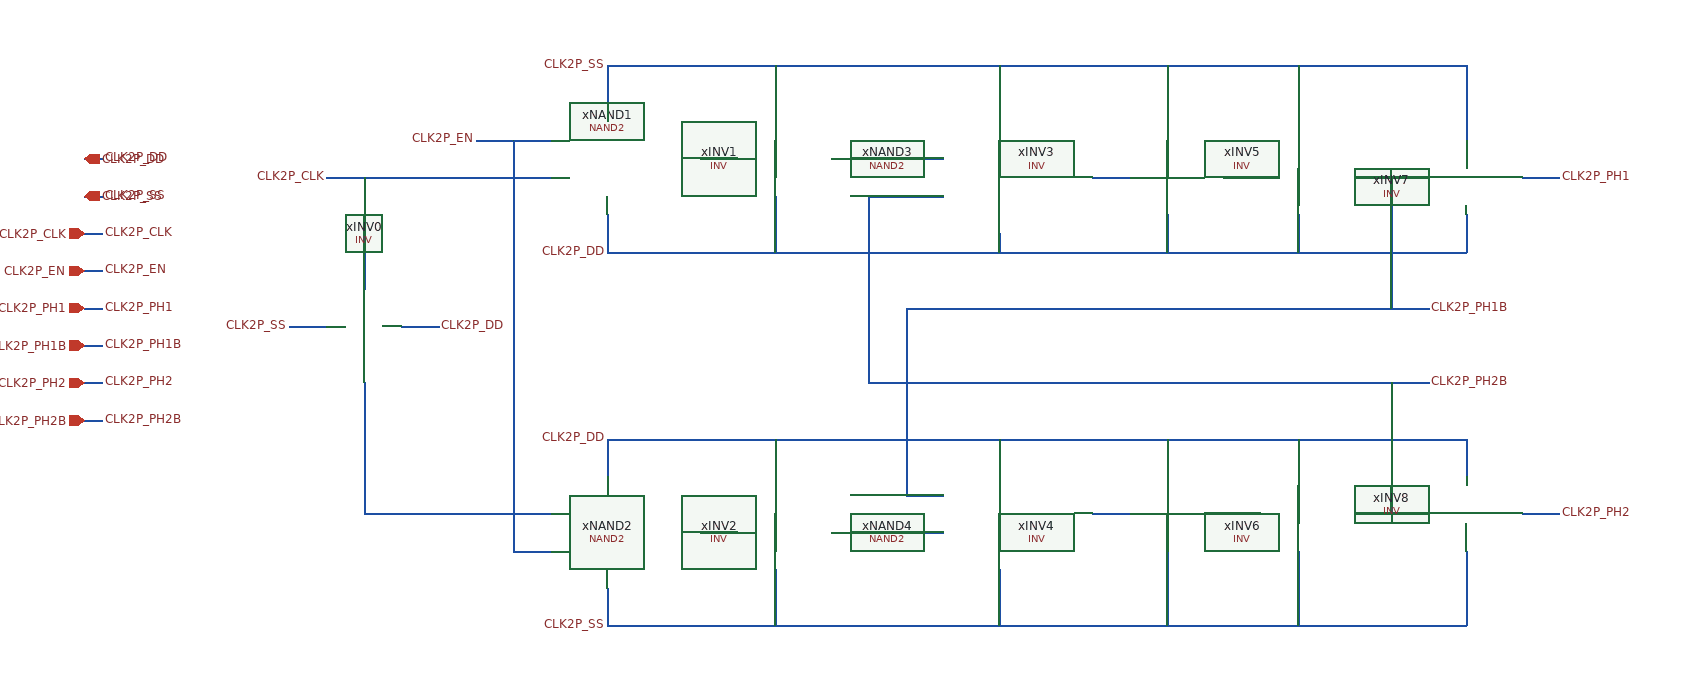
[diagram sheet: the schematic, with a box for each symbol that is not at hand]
v {xschem version=3.4.8RC file_version=1.3}
G {}
K {}
V {}
S {}
F {}
E {}
N 140 -660 160 -660 {lab=CLK2P_DD}
N 140 -620 160 -620 {lab=CLK2P_SS}
N 140 -580 160 -580 {lab=CLK2P_CLK}
N 140 -540 160 -540 {lab=CLK2P_EN}
N 140 -500 160 -500 {lab=CLK2P_PH1}
N 140 -460 160 -460 {lab=CLK2P_PH1B}
N 140 -420 160 -420 {lab=CLK2P_PH2}
N 140 -380 160 -380 {lab=CLK2P_PH2B}
N 700 -760 700 -720 {lab=CLK2P_SS}
N 700 -200 700 -160 {lab=CLK2P_SS}
N 700 -360 700 -320 {lab=CLK2P_DD}
N 700 -600 700 -560 {lab=CLK2P_DD}
N 800 -660 840 -660 {lab=#net1}
N 800 -260 840 -260 {lab=#net2}
N 560 -680 640 -680 {lab=#net3}
N 400 -640 640 -640 {lab=CLK2P_CLK}
N 440 -280 640 -280 {lab=#net4}
N 440 -640 440 -520 {lab=CLK2P_CLK}
N 360 -480 400 -480 {lab=CLK2P_SS}
N 480 -480 520 -480 {lab=CLK2P_DD}
N 1220 -640 1260 -640 {lab=#net5}
N 1220 -280 1260 -280 {lab=#net6}
N 1300 -600 1300 -560 {lab=CLK2P_DD}
N 1300 -360 1300 -320 {lab=CLK2P_DD}
N 1360 -640 1400 -640 {lab=#net7}
N 1360 -280 1400 -280 {lab=#net8}
N 1440 -600 1440 -560 {lab=CLK2P_DD}
N 1440 -360 1440 -320 {lab=CLK2P_DD}
N 440 -420 440 -280 {lab=#net4}
N 1500 -640 1580 -640 {lab=CLK2P_PH1B}
N 1500 -280 1580 -280 {lab=CLK2P_PH2B}
N 1620 -600 1620 -560 {lab=CLK2P_DD}
N 1620 -360 1620 -320 {lab=CLK2P_DD}
N 1680 -640 1720 -640 {lab=CLK2P_PH1}
N 1680 -280 1720 -280 {lab=CLK2P_PH2}
N 1020 -300 1060 -300 {lab=CLK2P_PH1B}
N 980 -620 1060 -620 {lab=CLK2P_PH2B}
N 940 -260 1060 -260 {lab=#net9}
N 940 -660 1060 -660 {lab=#net10}
N 980 -620 980 -420 {lab=CLK2P_PH2B}
N 1020 -500 1020 -300 {lab=CLK2P_PH1B}
N 1540 -640 1540 -500 {lab=CLK2P_PH1B}
N 1540 -420 1540 -280 {lab=CLK2P_PH2B}
N 980 -420 1580 -420 {lab=CLK2P_PH2B}
N 1020 -500 1580 -500 {lab=CLK2P_PH1B}
N 880 -360 880 -300 {lab=CLK2P_DD}
N 1120 -360 1120 -340 {lab=CLK2P_DD}
N 700 -360 1620 -360 {lab=CLK2P_DD}
N 880 -620 880 -560 {lab=CLK2P_DD}
N 1120 -580 1120 -560 {lab=CLK2P_DD}
N 700 -560 1620 -560 {lab=CLK2P_DD}
N 880 -220 880 -160 {lab=CLK2P_SS}
N 1120 -220 1120 -160 {lab=CLK2P_SS}
N 1300 -240 1300 -160 {lab=CLK2P_SS}
N 1440 -240 1440 -160 {lab=CLK2P_SS}
N 1620 -240 1620 -160 {lab=CLK2P_SS}
N 700 -160 1620 -160 {lab=CLK2P_SS}
N 1300 -760 1300 -680 {lab=CLK2P_SS}
N 1440 -760 1440 -680 {lab=CLK2P_SS}
N 1620 -760 1620 -680 {lab=CLK2P_SS}
N 1120 -760 1120 -700 {lab=CLK2P_SS}
N 880 -760 880 -700 {lab=CLK2P_SS}
N 700 -760 1620 -760 {lab=CLK2P_SS}
N 600 -240 640 -240 {lab=#net3}
N 600 -680 600 -240 {lab=#net3}
C {title.sym} 160 -40 0 0 {name=l1 author="Yi-Hsiang Wei"}
C {iopin.sym} 140 -660 0 1 {name=p8 lab=CLK2P_DD}
C {iopin.sym} 140 -620 0 1 {name=p9 lab=CLK2P_SS}
C {lab_wire.sym} 160 -660 0 1 {name=p11 sig_type=std_logic lab=CLK2P_DD}
C {lab_wire.sym} 160 -620 0 1 {name=p12 sig_type=std_logic lab=CLK2P_SS}
C {ipin.sym} 140 -580 0 0 {name=p13 lab=CLK2P_CLK}
C {lab_wire.sym} 160 -580 0 1 {name=p15 sig_type=std_logic lab=CLK2P_CLK}
C {ECG_Acquisition_IC/Design_Files/IC Design/Schematic/INV/INV.sym} 340 -600 1 0 {name=xINV0}
C {lab_wire.sym} 400 -640 0 0 {name=p5 sig_type=std_logic lab=CLK2P_CLK}
C {ipin.sym} 140 -540 0 0 {name=p1 lab=CLK2P_EN}
C {lab_wire.sym} 160 -540 0 1 {name=p2 sig_type=std_logic lab=CLK2P_EN}
C {opin.sym} 140 -500 0 1 {name=p3 lab=CLK2P_PH1}
C {lab_wire.sym} 160 -500 0 1 {name=p4 sig_type=std_logic lab=CLK2P_PH1}
C {opin.sym} 140 -460 0 1 {name=p6 lab=CLK2P_PH1B}
C {lab_wire.sym} 160 -460 0 1 {name=p7 sig_type=std_logic lab=CLK2P_PH1B}
C {opin.sym} 140 -420 0 1 {name=p10 lab=CLK2P_PH2}
C {lab_wire.sym} 160 -420 0 1 {name=p14 sig_type=std_logic lab=CLK2P_PH2}
C {opin.sym} 140 -380 0 1 {name=p16 lab=CLK2P_PH2B}
C {lab_wire.sym} 160 -380 0 1 {name=p17 sig_type=std_logic lab=CLK2P_PH2B}
C {ECG_Acquisition_IC/Design_Files/IC Design/Schematic/NAND2/NAND2.sym} 560 -740 2 1 {name=xNAND1}
C {ECG_Acquisition_IC/Design_Files/IC Design/Schematic/NAND2/NAND2.sym} 560 -180 0 0 {name=xNAND2}
C {ECG_Acquisition_IC/Design_Files/IC Design/Schematic/INV/INV.sym} 760 -760 2 1 {name=xINV1}
C {ECG_Acquisition_IC/Design_Files/IC Design/Schematic/INV/INV.sym} 760 -160 0 0 {name=xINV2}
C {lab_wire.sym} 560 -680 0 0 {name=p18 sig_type=std_logic lab=CLK2P_EN}
C {ECG_Acquisition_IC/Design_Files/IC Design/Schematic/NAND2/NAND2.sym} 980 -720 2 1 {name=xNAND3}
C {ECG_Acquisition_IC/Design_Files/IC Design/Schematic/NAND2/NAND2.sym} 980 -200 0 0 {name=xNAND4}
C {ECG_Acquisition_IC/Design_Files/IC Design/Schematic/INV/INV.sym} 1180 -740 2 1 {name=xINV3}
C {ECG_Acquisition_IC/Design_Files/IC Design/Schematic/INV/INV.sym} 1180 -180 0 0 {name=xINV4}
C {ECG_Acquisition_IC/Design_Files/IC Design/Schematic/INV/INV.sym} 1320 -740 2 1 {name=xINV5}
C {ECG_Acquisition_IC/Design_Files/IC Design/Schematic/INV/INV.sym} 1320 -180 0 0 {name=xINV6}
C {lab_wire.sym} 1580 -500 2 0 {name=p20 sig_type=std_logic lab=CLK2P_PH1B}
C {ECG_Acquisition_IC/Design_Files/IC Design/Schematic/INV/INV.sym} 1500 -740 2 1 {name=xINV7}
C {ECG_Acquisition_IC/Design_Files/IC Design/Schematic/INV/INV.sym} 1500 -180 0 0 {name=xINV8}
C {lab_wire.sym} 1580 -420 0 1 {name=p21 sig_type=std_logic lab=CLK2P_PH2B}
C {lab_wire.sym} 1720 -280 2 0 {name=p22 sig_type=std_logic lab=CLK2P_PH2}
C {lab_wire.sym} 1720 -640 0 1 {name=p23 sig_type=std_logic lab=CLK2P_PH1}
C {lab_wire.sym} 700 -360 0 0 {name=p24 sig_type=std_logic lab=CLK2P_DD}
C {lab_wire.sym} 700 -560 2 1 {name=p25 sig_type=std_logic lab=CLK2P_DD}
C {lab_wire.sym} 700 -160 2 1 {name=p26 sig_type=std_logic lab=CLK2P_SS}
C {lab_wire.sym} 700 -760 0 0 {name=p27 sig_type=std_logic lab=CLK2P_SS}
C {lab_wire.sym} 360 -480 0 0 {name=p28 sig_type=std_logic lab=CLK2P_SS}
C {lab_wire.sym} 520 -480 0 1 {name=p29 sig_type=std_logic lab=CLK2P_DD}
